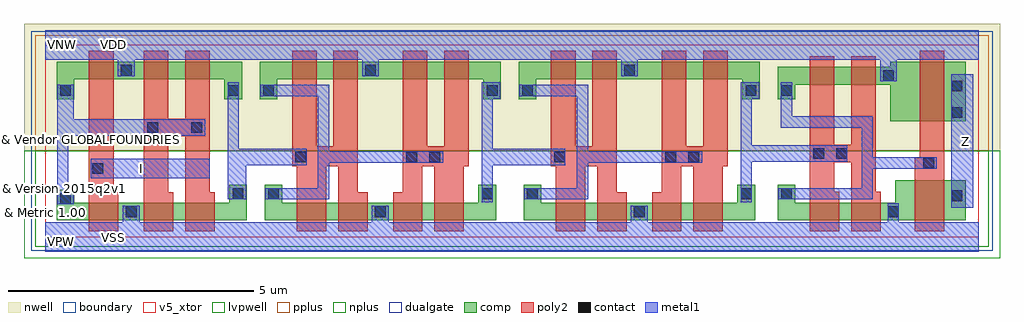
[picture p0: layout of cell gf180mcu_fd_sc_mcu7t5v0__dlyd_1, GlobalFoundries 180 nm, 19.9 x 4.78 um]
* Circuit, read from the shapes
.subckt gf180mcu_fd_sc_mcu7t5v0__dlyd_1 I VDD VNW VSS Z
XM1 VSS I n1 VSUBS nfet_05v0 w=0.36u l=0.6u
XM2 n2 n1 VSS VSUBS nfet_05v0 w=0.36u l=0.6u
XM3 n3 n1 n2 VSUBS nfet_05v0 w=0.36u l=0.6u
XM4 n4 n3 n5 VSUBS nfet_05v0 w=0.36u l=0.6u
XM5 VSS n3 n4 VSUBS nfet_05v0 w=0.36u l=0.6u
XM6 n6 n5 VSS VSUBS nfet_05v0 w=0.36u l=0.6u
XM7 n7 n5 n6 VSUBS nfet_05v0 w=0.36u l=0.6u
XM8 n8 n7 n9 VSUBS nfet_05v0 w=0.36u l=0.6u
XM9 VSS n7 n8 VSUBS nfet_05v0 w=0.36u l=0.6u
XM10 n10 n9 VSS VSUBS nfet_05v0 w=0.36u l=0.6u
XM11 n11 n9 n10 VSUBS nfet_05v0 w=0.36u l=0.6u
XM12 n12 n11 n13 VSUBS nfet_05v0 w=0.365u l=0.6u
XM13 VSS n11 n12 VSUBS nfet_05v0 w=0.365u l=0.6u
XM14 Z n13 VSS VSUBS nfet_05v0 w=0.82u l=0.6u
XM15 VDD I n1 VNW pfet_05v0 w=0.36u l=0.5u
XM16 n14 n1 VDD VNW pfet_05v0 w=0.36u l=0.5u
XM17 n3 n1 n14 VNW pfet_05v0 w=0.36u l=0.5u
XM18 n15 n3 n5 VNW pfet_05v0 w=0.36u l=0.5u
XM19 VDD n3 n15 VNW pfet_05v0 w=0.36u l=0.5u
XM20 n16 n5 VDD VNW pfet_05v0 w=0.36u l=0.5u
XM21 n7 n5 n16 VNW pfet_05v0 w=0.36u l=0.5u
XM22 n17 n7 n9 VNW pfet_05v0 w=0.36u l=0.5u
XM23 VDD n7 n17 VNW pfet_05v0 w=0.36u l=0.5u
XM24 n18 n9 VDD VNW pfet_05v0 w=0.36u l=0.5u
XM25 n11 n9 n18 VNW pfet_05v0 w=0.36u l=0.5u
XM26 n19 n11 n13 VNW pfet_05v0 w=0.36u l=0.5u
XM27 VDD n11 n19 VNW pfet_05v0 w=0.36u l=0.5u
XM28 Z n13 VDD VNW pfet_05v0 w=1.22u l=0.5u
.ends

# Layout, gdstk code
import gdstk
lib = gdstk.Library(unit=1e-6, precision=5e-09)
def R(c, l, rs):  # rectangles x0, y0, x1, y1
    for r in rs: c.add(gdstk.rectangle(r[:2], r[2:], *l))
def P(c, l, *ps):  # polygons
    for p in ps: c.add(gdstk.Polygon(p, *l))
boundary = (0, 0)
nwell = (21, 0)
comp = (22, 0)
poly2 = (30, 0)
pplus = (31, 0)
nplus = (32, 0)
contact = (33, 0)
metal1 = (34, 0)
dualgate = (55, 0)
v5_xtor = (112, 1)
lvpwell = (204, 0)

gf180mcu_fd_sc_mcu7t5v0_ = lib.new_cell('gf180mcu_fd_sc_mcu7t5v0__dlyd_1')
R(gf180mcu_fd_sc_mcu7t5v0_, boundary, [(0,0,19.04,3.92)])
R(gf180mcu_fd_sc_mcu7t5v0_, nwell, [(-0.43,1.76,19.47,4.35)])
P(gf180mcu_fd_sc_mcu7t5v0_, comp, [(0.235,2.81),(0.235,3.58),(4.015,3.58),(4.015,2.81),(3.655,2.81),(3.655,3.22),(0.595,3.22),(0.595,2.81)],
  [(0.235,0.34),(0.235,0.965),(0.595,0.965),(0.595,0.7),(3.755,0.7),(3.755,1.065),(4.115,1.065),(4.115,0.34)],
  [(4.475,0.34),(4.475,1.065),(4.835,1.065),(4.835,0.7),(8.835,0.7),(8.835,1.065),(9.195,1.065),(9.195,0.34)],
  [(4.375,2.81),(4.375,3.58),(9.295,3.58),(9.295,2.81),(8.935,2.81),(8.935,3.22),(4.735,3.22),(4.735,2.81)],
  [(9.755,0.34),(9.755,1.065),(10.115,1.065),(10.115,0.7),(14.115,0.7),(14.115,1.065),(14.475,1.065),(14.475,0.34)],
  [(9.655,2.81),(9.655,3.58),(14.575,3.58),(14.575,2.81),(14.215,2.81),(14.215,3.22),(10.015,3.22),(10.015,2.81)],
  [(14.935,0.34),(14.935,1.065),(15.295,1.065),(15.295,0.705),(17.335,0.705),(17.335,1.16),(18.775,1.16),(18.775,0.34)],
  [(17.235,2.36),(17.235,3.11),(15.295,3.11),(15.295,2.81),(14.935,2.81),(14.935,3.47),(17.235,3.47),(17.235,3.58),(18.775,3.58),(18.775,2.36)])
P(gf180mcu_fd_sc_mcu7t5v0_, poly2, [(0.895,0.12),(0.895,3.8),(1.395,3.8),(1.395,0.92),(1.495,0.92),(1.495,0.12)],
  [(2.015,0.12),(2.015,3.8),(2.515,3.8),(2.515,2.415),(2.855,2.415),(2.855,3.8),(3.355,3.8),(3.355,0.92),(3.455,0.92),(3.455,0.12),(2.855,0.12),(2.855,2.055),(2.515,2.055),(2.515,0.92),(2.615,0.92),(2.615,0.12)],
  [(5.135,0.12),(5.135,1.45),(5.035,1.45),(5.035,3.8),(5.535,3.8),(5.535,1.855),(5.875,1.855),(5.875,3.8),(6.375,3.8),(6.375,0.92),(6.575,0.92),(6.575,0.12),(5.975,0.12),(5.975,1.45),(5.735,1.45),(5.735,0.12)],
  [(7.095,0.12),(7.095,0.92),(7.295,0.92),(7.295,3.8),(7.795,3.8),(7.795,1.855),(8.135,1.855),(8.135,3.8),(8.635,3.8),(8.635,1.45),(8.535,1.45),(8.535,0.12),(7.935,0.12),(7.935,1.45),(7.695,1.45),(7.695,0.12)],
  [(10.415,0.12),(10.415,1.45),(10.315,1.45),(10.315,3.8),(10.815,3.8),(10.815,1.855),(11.155,1.855),(11.155,3.8),(11.655,3.8),(11.655,0.92),(11.855,0.92),(11.855,0.12),(11.255,0.12),(11.255,1.45),(11.015,1.45),(11.015,0.12)],
  [(12.375,0.12),(12.375,0.92),(12.575,0.92),(12.575,3.8),(13.075,3.8),(13.075,1.855),(13.415,1.855),(13.415,3.8),(13.915,3.8),(13.915,1.45),(13.815,1.45),(13.815,0.12),(13.215,0.12),(13.215,1.45),(12.975,1.45),(12.975,0.12)],
  [(15.595,0.12),(15.595,3.69),(16.095,3.69),(16.095,1.885),(16.435,1.885),(16.435,3.69),(16.935,3.69),(16.935,0.925),(17.035,0.925),(17.035,0.12),(16.435,0.12),(16.435,1.525),(16.095,1.525),(16.095,0.925),(16.195,0.925),(16.195,0.12)],
  [(17.735,0.12),(17.735,1.615),(17.835,1.615),(17.835,3.8),(18.335,3.8),(18.335,0.12)])
R(gf180mcu_fd_sc_mcu7t5v0_, pplus, [(-0.2,1.76,19.24,4.12)])
R(gf180mcu_fd_sc_mcu7t5v0_, nplus, [(-0.2,-0.2,19.24,1.76)])
R(gf180mcu_fd_sc_mcu7t5v0_, contact, [(1.645,0.41,1.865,0.63), (6.725,0.41,6.945,0.63), (12.005,0.41,12.225,0.63), (17.185,0.41,17.405,0.63), (0.305,0.675,0.525,0.895), (18.485,0.735,18.705,0.955), (3.825,0.775,4.045,0.995), (4.545,0.775,4.765,0.995), (8.905,0.775,9.125,0.995), (9.825,0.775,10.045,0.995), (14.185,0.775,14.405,0.995), (15.005,0.775,15.225,0.995), (0.965,1.29,1.185,1.51), (17.905,1.4,18.125,1.62), (5.105,1.525,5.325,1.745), (7.365,1.525,7.585,1.745), (7.835,1.525,8.055,1.745), (10.385,1.525,10.605,1.745), (12.645,1.525,12.865,1.745), (13.115,1.525,13.335,1.745), (15.665,1.595,15.885,1.815), (16.135,1.595,16.355,1.815), (2.085,2.125,2.305,2.345), (2.985,2.125,3.205,2.345), (18.485,2.43,18.705,2.65), (0.305,2.88,0.525,3.1), (3.725,2.88,3.945,3.1), (4.445,2.88,4.665,3.1), (9.005,2.88,9.225,3.1), (9.725,2.88,9.945,3.1), (14.285,2.88,14.505,3.1), (15.005,2.88,15.225,3.1), (18.485,2.97,18.705,3.19), (17.085,3.18,17.305,3.4), (1.545,3.29,1.765,3.51), (6.525,3.29,6.745,3.51), (11.805,3.29,12.025,3.51)])
R(gf180mcu_fd_sc_mcu7t5v0_, metal1, [(18.48,0.6,18.92,3.32), (0.93,1.2,3.355,1.6)])
P(gf180mcu_fd_sc_mcu7t5v0_, metal1, [(0.245,0.67),(0.245,3.105),(0.585,3.105),(0.585,2.405),(3.265,2.405),(3.265,2.065),(0.475,2.065),(0.475,0.9),(0.585,0.9),(0.585,0.67)],
  [(3.72,0.77),(3.72,3.16),(3.95,3.16),(3.95,1.805),(5.33,1.805),(5.33,1.465),(4.105,1.465),(4.105,0.77)],
  [(4.485,0.77),(4.485,1),(5.56,1),(5.56,2.875),(4.385,2.875),(4.385,3.105),(5.79,3.105),(5.79,1.75),(8.115,1.75),(8.115,1.52),(5.79,1.52),(5.79,0.77)],
  [(8.9,0.715),(8.9,3.16),(9.285,3.16),(9.285,2.82),(9.13,2.82),(9.13,1.805),(10.61,1.805),(10.61,1.465),(9.13,1.465),(9.13,0.715)],
  [(9.765,0.77),(9.765,1),(10.84,1),(10.84,2.875),(9.665,2.875),(9.665,3.105),(11.07,3.105),(11.07,1.75),(13.395,1.75),(13.395,1.52),(11.07,1.52),(11.07,0.77)],
  [(14.18,0.715),(14.18,3.16),(14.565,3.16),(14.565,2.82),(14.41,2.82),(14.41,1.875),(16.36,1.875),(16.36,1.535),(14.41,1.535),(14.41,0.715)],
  [(14.945,0.77),(14.945,1),(16.65,1),(16.65,2.235),(15,2.235),(15,3.16),(15.23,3.16),(15.23,2.465),(16.88,2.465),(16.88,1.625),(18.185,1.625),(18.185,1.395),(16.88,1.395),(16.88,0.77)],
  [(0,-0.3),(0,0.3),(1.585,0.3),(1.585,0.635),(1.925,0.635),(1.925,0.3),(6.665,0.3),(6.665,0.635),(7.005,0.635),(7.005,0.3),(11.945,0.3),(11.945,0.635),(12.285,0.635),(12.285,0.3),(17.18,0.3),(17.18,0.69),(17.41,0.69),(17.41,0.3),(19.04,0.3),(19.04,-0.3)],
  [(17.025,3.175),(17.025,3.62),(12.085,3.62),(12.085,3.285),(11.745,3.285),(11.745,3.62),(6.805,3.62),(6.805,3.285),(6.465,3.285),(6.465,3.62),(1.825,3.62),(1.825,3.285),(1.485,3.285),(1.485,3.62),(0,3.62),(0,4.22),(19.04,4.22),(19.04,3.62),(17.365,3.62),(17.365,3.175)])
R(gf180mcu_fd_sc_mcu7t5v0_, dualgate, [(-0.28,-0.28,19.32,4.2)])
R(gf180mcu_fd_sc_mcu7t5v0_, v5_xtor, [(0,0,19.04,3.92)])
R(gf180mcu_fd_sc_mcu7t5v0_, lvpwell, [(-0.43,-0.43,19.47,1.76)])
gf180mcu_fd_sc_mcu7t5v0_.add(gdstk.Label('VDD', (1.4,3.92), layer=34, texttype=10))
gf180mcu_fd_sc_mcu7t5v0_.add(gdstk.Label('I', (1.96,1.4), layer=34, texttype=10))
gf180mcu_fd_sc_mcu7t5v0_.add(gdstk.Label('VSS', (1.4,0), layer=34, texttype=10))
gf180mcu_fd_sc_mcu7t5v0_.add(gdstk.Label('Z', (18.76,1.96), layer=34, texttype=10))
gf180mcu_fd_sc_mcu7t5v0_.add(gdstk.Label('& Vendor GLOBALFOUNDRIES', (0,2), layer=63, texttype=63))
gf180mcu_fd_sc_mcu7t5v0_.add(gdstk.Label('& Product GF018hv5v_mcu_sc7', (0,1.5), layer=63, texttype=63))
gf180mcu_fd_sc_mcu7t5v0_.add(gdstk.Label('& Version 2015q2v1', (0,1), layer=63, texttype=63))
gf180mcu_fd_sc_mcu7t5v0_.add(gdstk.Label('& Metric 1.00', (0,0.5), layer=63, texttype=63))
gf180mcu_fd_sc_mcu7t5v0_.add(gdstk.Label('VNW', (0.345,3.92), layer=21, texttype=10))
gf180mcu_fd_sc_mcu7t5v0_.add(gdstk.Label('VPW', (0.34,-0.085), layer=204, texttype=10))

lib.write_gds('gf180mcu_fd_sc_mcu7t5v0__dlyd_1.gds')
